# Generated by FakeRAM 2.0
VERSION 5.7 ;
BUSBITCHARS "[]" ;
PROPERTYDEFINITIONS
  MACRO width INTEGER ;
  MACRO depth INTEGER ;
  MACRO banks INTEGER ;
END PROPERTYDEFINITIONS
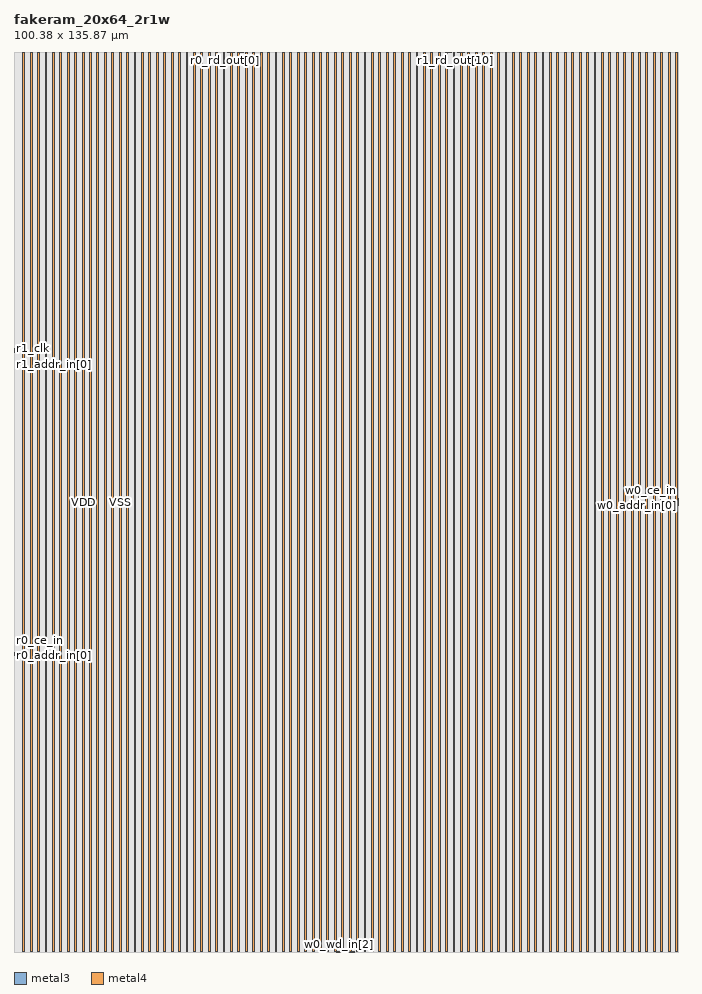
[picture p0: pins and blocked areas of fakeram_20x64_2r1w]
MACRO fakeram_20x64_2r1w
  PROPERTY width 20 ;
  PROPERTY depth 64 ;
  PROPERTY banks 1 ;
  FOREIGN fakeram_20x64_2r1w 0 0 ;
  SYMMETRY X Y R90 ;
  SIZE 100.380 BY 135.870 ;
  CLASS BLOCK ;
  PIN r0_addr_in[0]
    DIRECTION INPUT ;
    USE SIGNAL ;
    SHAPE ABUTMENT ;
    PORT
      LAYER metal3 ;
      RECT 0.000 44.800 0.070 44.870 ;
    END
  END r0_addr_in[0]
  PIN r0_addr_in[1]
    DIRECTION INPUT ;
    USE SIGNAL ;
    SHAPE ABUTMENT ;
    PORT
      LAYER metal3 ;
      RECT 0.000 44.940 0.070 45.010 ;
    END
  END r0_addr_in[1]
  PIN r0_addr_in[2]
    DIRECTION INPUT ;
    USE SIGNAL ;
    SHAPE ABUTMENT ;
    PORT
      LAYER metal3 ;
      RECT 0.000 45.080 0.070 45.150 ;
    END
  END r0_addr_in[2]
  PIN r0_addr_in[3]
    DIRECTION INPUT ;
    USE SIGNAL ;
    SHAPE ABUTMENT ;
    PORT
      LAYER metal3 ;
      RECT 0.000 45.220 0.070 45.290 ;
    END
  END r0_addr_in[3]
  PIN r0_addr_in[4]
    DIRECTION INPUT ;
    USE SIGNAL ;
    SHAPE ABUTMENT ;
    PORT
      LAYER metal3 ;
      RECT 0.000 45.360 0.070 45.430 ;
    END
  END r0_addr_in[4]
  PIN r0_addr_in[5]
    DIRECTION INPUT ;
    USE SIGNAL ;
    SHAPE ABUTMENT ;
    PORT
      LAYER metal3 ;
      RECT 0.000 45.500 0.070 45.570 ;
    END
  END r0_addr_in[5]
  PIN r0_ce_in
    DIRECTION INPUT ;
    USE SIGNAL ;
    SHAPE ABUTMENT ;
    PORT
      LAYER metal3 ;
      RECT 0.000 45.780 0.070 45.850 ;
    END
  END r0_ce_in
  PIN r0_clk
    DIRECTION INPUT ;
    USE SIGNAL ;
    SHAPE ABUTMENT ;
    PORT
      LAYER metal3 ;
      RECT 0.000 45.920 0.070 45.990 ;
    END
  END r0_clk
  PIN r0_rd_out[0]
    DIRECTION OUTPUT ;
    USE SIGNAL ;
    SHAPE ABUTMENT ;
    PORT
      LAYER metal3 ;
      RECT 31.885 135.800 31.955 135.870 ;
    END
  END r0_rd_out[0]
  PIN r0_rd_out[1]
    DIRECTION OUTPUT ;
    USE SIGNAL ;
    SHAPE ABUTMENT ;
    PORT
      LAYER metal3 ;
      RECT 32.025 135.800 32.095 135.870 ;
    END
  END r0_rd_out[1]
  PIN r0_rd_out[2]
    DIRECTION OUTPUT ;
    USE SIGNAL ;
    SHAPE ABUTMENT ;
    PORT
      LAYER metal3 ;
      RECT 32.165 135.800 32.235 135.870 ;
    END
  END r0_rd_out[2]
  PIN r0_rd_out[3]
    DIRECTION OUTPUT ;
    USE SIGNAL ;
    SHAPE ABUTMENT ;
    PORT
      LAYER metal3 ;
      RECT 32.305 135.800 32.375 135.870 ;
    END
  END r0_rd_out[3]
  PIN r0_rd_out[4]
    DIRECTION OUTPUT ;
    USE SIGNAL ;
    SHAPE ABUTMENT ;
    PORT
      LAYER metal3 ;
      RECT 32.445 135.800 32.515 135.870 ;
    END
  END r0_rd_out[4]
  PIN r0_rd_out[5]
    DIRECTION OUTPUT ;
    USE SIGNAL ;
    SHAPE ABUTMENT ;
    PORT
      LAYER metal3 ;
      RECT 32.585 135.800 32.655 135.870 ;
    END
  END r0_rd_out[5]
  PIN r0_rd_out[6]
    DIRECTION OUTPUT ;
    USE SIGNAL ;
    SHAPE ABUTMENT ;
    PORT
      LAYER metal3 ;
      RECT 32.725 135.800 32.795 135.870 ;
    END
  END r0_rd_out[6]
  PIN r0_rd_out[7]
    DIRECTION OUTPUT ;
    USE SIGNAL ;
    SHAPE ABUTMENT ;
    PORT
      LAYER metal3 ;
      RECT 32.865 135.800 32.935 135.870 ;
    END
  END r0_rd_out[7]
  PIN r0_rd_out[8]
    DIRECTION OUTPUT ;
    USE SIGNAL ;
    SHAPE ABUTMENT ;
    PORT
      LAYER metal3 ;
      RECT 33.005 135.800 33.075 135.870 ;
    END
  END r0_rd_out[8]
  PIN r0_rd_out[9]
    DIRECTION OUTPUT ;
    USE SIGNAL ;
    SHAPE ABUTMENT ;
    PORT
      LAYER metal3 ;
      RECT 33.145 135.800 33.215 135.870 ;
    END
  END r0_rd_out[9]
  PIN r0_rd_out[10]
    DIRECTION OUTPUT ;
    USE SIGNAL ;
    SHAPE ABUTMENT ;
    PORT
      LAYER metal3 ;
      RECT 33.285 135.800 33.355 135.870 ;
    END
  END r0_rd_out[10]
  PIN r0_rd_out[11]
    DIRECTION OUTPUT ;
    USE SIGNAL ;
    SHAPE ABUTMENT ;
    PORT
      LAYER metal3 ;
      RECT 33.425 135.800 33.495 135.870 ;
    END
  END r0_rd_out[11]
  PIN r0_rd_out[12]
    DIRECTION OUTPUT ;
    USE SIGNAL ;
    SHAPE ABUTMENT ;
    PORT
      LAYER metal3 ;
      RECT 33.565 135.800 33.635 135.870 ;
    END
  END r0_rd_out[12]
  PIN r0_rd_out[13]
    DIRECTION OUTPUT ;
    USE SIGNAL ;
    SHAPE ABUTMENT ;
    PORT
      LAYER metal3 ;
      RECT 33.705 135.800 33.775 135.870 ;
    END
  END r0_rd_out[13]
  PIN r0_rd_out[14]
    DIRECTION OUTPUT ;
    USE SIGNAL ;
    SHAPE ABUTMENT ;
    PORT
      LAYER metal3 ;
      RECT 33.845 135.800 33.915 135.870 ;
    END
  END r0_rd_out[14]
  PIN r0_rd_out[15]
    DIRECTION OUTPUT ;
    USE SIGNAL ;
    SHAPE ABUTMENT ;
    PORT
      LAYER metal3 ;
      RECT 33.985 135.800 34.055 135.870 ;
    END
  END r0_rd_out[15]
  PIN r0_rd_out[16]
    DIRECTION OUTPUT ;
    USE SIGNAL ;
    SHAPE ABUTMENT ;
    PORT
      LAYER metal3 ;
      RECT 34.125 135.800 34.195 135.870 ;
    END
  END r0_rd_out[16]
  PIN r0_rd_out[17]
    DIRECTION OUTPUT ;
    USE SIGNAL ;
    SHAPE ABUTMENT ;
    PORT
      LAYER metal3 ;
      RECT 34.265 135.800 34.335 135.870 ;
    END
  END r0_rd_out[17]
  PIN r0_rd_out[18]
    DIRECTION OUTPUT ;
    USE SIGNAL ;
    SHAPE ABUTMENT ;
    PORT
      LAYER metal3 ;
      RECT 34.405 135.800 34.475 135.870 ;
    END
  END r0_rd_out[18]
  PIN r0_rd_out[19]
    DIRECTION OUTPUT ;
    USE SIGNAL ;
    SHAPE ABUTMENT ;
    PORT
      LAYER metal3 ;
      RECT 34.545 135.800 34.615 135.870 ;
    END
  END r0_rd_out[19]
  PIN r1_addr_in[0]
    DIRECTION INPUT ;
    USE SIGNAL ;
    SHAPE ABUTMENT ;
    PORT
      LAYER metal3 ;
      RECT 0.000 89.880 0.070 89.950 ;
    END
  END r1_addr_in[0]
  PIN r1_addr_in[1]
    DIRECTION INPUT ;
    USE SIGNAL ;
    SHAPE ABUTMENT ;
    PORT
      LAYER metal3 ;
      RECT 0.000 90.020 0.070 90.090 ;
    END
  END r1_addr_in[1]
  PIN r1_addr_in[2]
    DIRECTION INPUT ;
    USE SIGNAL ;
    SHAPE ABUTMENT ;
    PORT
      LAYER metal3 ;
      RECT 0.000 90.160 0.070 90.230 ;
    END
  END r1_addr_in[2]
  PIN r1_addr_in[3]
    DIRECTION INPUT ;
    USE SIGNAL ;
    SHAPE ABUTMENT ;
    PORT
      LAYER metal3 ;
      RECT 0.000 90.300 0.070 90.370 ;
    END
  END r1_addr_in[3]
  PIN r1_addr_in[4]
    DIRECTION INPUT ;
    USE SIGNAL ;
    SHAPE ABUTMENT ;
    PORT
      LAYER metal3 ;
      RECT 0.000 90.440 0.070 90.510 ;
    END
  END r1_addr_in[4]
  PIN r1_addr_in[5]
    DIRECTION INPUT ;
    USE SIGNAL ;
    SHAPE ABUTMENT ;
    PORT
      LAYER metal3 ;
      RECT 0.000 90.580 0.070 90.650 ;
    END
  END r1_addr_in[5]
  PIN r1_ce_in
    DIRECTION INPUT ;
    USE SIGNAL ;
    SHAPE ABUTMENT ;
    PORT
      LAYER metal3 ;
      RECT 0.000 90.860 0.070 90.930 ;
    END
  END r1_ce_in
  PIN r1_clk
    DIRECTION INPUT ;
    USE SIGNAL ;
    SHAPE ABUTMENT ;
    PORT
      LAYER metal3 ;
      RECT 0.000 91.000 0.070 91.070 ;
    END
  END r1_clk
  PIN r1_rd_out[0]
    DIRECTION OUTPUT ;
    USE SIGNAL ;
    SHAPE ABUTMENT ;
    PORT
      LAYER metal3 ;
      RECT 65.205 135.800 65.275 135.870 ;
    END
  END r1_rd_out[0]
  PIN r1_rd_out[1]
    DIRECTION OUTPUT ;
    USE SIGNAL ;
    SHAPE ABUTMENT ;
    PORT
      LAYER metal3 ;
      RECT 65.345 135.800 65.415 135.870 ;
    END
  END r1_rd_out[1]
  PIN r1_rd_out[2]
    DIRECTION OUTPUT ;
    USE SIGNAL ;
    SHAPE ABUTMENT ;
    PORT
      LAYER metal3 ;
      RECT 65.485 135.800 65.555 135.870 ;
    END
  END r1_rd_out[2]
  PIN r1_rd_out[3]
    DIRECTION OUTPUT ;
    USE SIGNAL ;
    SHAPE ABUTMENT ;
    PORT
      LAYER metal3 ;
      RECT 65.625 135.800 65.695 135.870 ;
    END
  END r1_rd_out[3]
  PIN r1_rd_out[4]
    DIRECTION OUTPUT ;
    USE SIGNAL ;
    SHAPE ABUTMENT ;
    PORT
      LAYER metal3 ;
      RECT 65.765 135.800 65.835 135.870 ;
    END
  END r1_rd_out[4]
  PIN r1_rd_out[5]
    DIRECTION OUTPUT ;
    USE SIGNAL ;
    SHAPE ABUTMENT ;
    PORT
      LAYER metal3 ;
      RECT 65.905 135.800 65.975 135.870 ;
    END
  END r1_rd_out[5]
  PIN r1_rd_out[6]
    DIRECTION OUTPUT ;
    USE SIGNAL ;
    SHAPE ABUTMENT ;
    PORT
      LAYER metal3 ;
      RECT 66.045 135.800 66.115 135.870 ;
    END
  END r1_rd_out[6]
  PIN r1_rd_out[7]
    DIRECTION OUTPUT ;
    USE SIGNAL ;
    SHAPE ABUTMENT ;
    PORT
      LAYER metal3 ;
      RECT 66.185 135.800 66.255 135.870 ;
    END
  END r1_rd_out[7]
  PIN r1_rd_out[8]
    DIRECTION OUTPUT ;
    USE SIGNAL ;
    SHAPE ABUTMENT ;
    PORT
      LAYER metal3 ;
      RECT 66.325 135.800 66.395 135.870 ;
    END
  END r1_rd_out[8]
  PIN r1_rd_out[9]
    DIRECTION OUTPUT ;
    USE SIGNAL ;
    SHAPE ABUTMENT ;
    PORT
      LAYER metal3 ;
      RECT 66.465 135.800 66.535 135.870 ;
    END
  END r1_rd_out[9]
  PIN r1_rd_out[10]
    DIRECTION OUTPUT ;
    USE SIGNAL ;
    SHAPE ABUTMENT ;
    PORT
      LAYER metal3 ;
      RECT 66.605 135.800 66.675 135.870 ;
    END
  END r1_rd_out[10]
  PIN r1_rd_out[11]
    DIRECTION OUTPUT ;
    USE SIGNAL ;
    SHAPE ABUTMENT ;
    PORT
      LAYER metal3 ;
      RECT 66.745 135.800 66.815 135.870 ;
    END
  END r1_rd_out[11]
  PIN r1_rd_out[12]
    DIRECTION OUTPUT ;
    USE SIGNAL ;
    SHAPE ABUTMENT ;
    PORT
      LAYER metal3 ;
      RECT 66.885 135.800 66.955 135.870 ;
    END
  END r1_rd_out[12]
  PIN r1_rd_out[13]
    DIRECTION OUTPUT ;
    USE SIGNAL ;
    SHAPE ABUTMENT ;
    PORT
      LAYER metal3 ;
      RECT 67.025 135.800 67.095 135.870 ;
    END
  END r1_rd_out[13]
  PIN r1_rd_out[14]
    DIRECTION OUTPUT ;
    USE SIGNAL ;
    SHAPE ABUTMENT ;
    PORT
      LAYER metal3 ;
      RECT 67.165 135.800 67.235 135.870 ;
    END
  END r1_rd_out[14]
  PIN r1_rd_out[15]
    DIRECTION OUTPUT ;
    USE SIGNAL ;
    SHAPE ABUTMENT ;
    PORT
      LAYER metal3 ;
      RECT 67.305 135.800 67.375 135.870 ;
    END
  END r1_rd_out[15]
  PIN r1_rd_out[16]
    DIRECTION OUTPUT ;
    USE SIGNAL ;
    SHAPE ABUTMENT ;
    PORT
      LAYER metal3 ;
      RECT 67.445 135.800 67.515 135.870 ;
    END
  END r1_rd_out[16]
  PIN r1_rd_out[17]
    DIRECTION OUTPUT ;
    USE SIGNAL ;
    SHAPE ABUTMENT ;
    PORT
      LAYER metal3 ;
      RECT 67.585 135.800 67.655 135.870 ;
    END
  END r1_rd_out[17]
  PIN r1_rd_out[18]
    DIRECTION OUTPUT ;
    USE SIGNAL ;
    SHAPE ABUTMENT ;
    PORT
      LAYER metal3 ;
      RECT 67.725 135.800 67.795 135.870 ;
    END
  END r1_rd_out[18]
  PIN r1_rd_out[19]
    DIRECTION OUTPUT ;
    USE SIGNAL ;
    SHAPE ABUTMENT ;
    PORT
      LAYER metal3 ;
      RECT 67.865 135.800 67.935 135.870 ;
    END
  END r1_rd_out[19]
  PIN w0_addr_in[0]
    DIRECTION INPUT ;
    USE SIGNAL ;
    SHAPE ABUTMENT ;
    PORT
      LAYER metal3 ;
      RECT 100.310 67.340 100.380 67.410 ;
    END
  END w0_addr_in[0]
  PIN w0_addr_in[1]
    DIRECTION INPUT ;
    USE SIGNAL ;
    SHAPE ABUTMENT ;
    PORT
      LAYER metal3 ;
      RECT 100.310 67.480 100.380 67.550 ;
    END
  END w0_addr_in[1]
  PIN w0_addr_in[2]
    DIRECTION INPUT ;
    USE SIGNAL ;
    SHAPE ABUTMENT ;
    PORT
      LAYER metal3 ;
      RECT 100.310 67.620 100.380 67.690 ;
    END
  END w0_addr_in[2]
  PIN w0_addr_in[3]
    DIRECTION INPUT ;
    USE SIGNAL ;
    SHAPE ABUTMENT ;
    PORT
      LAYER metal3 ;
      RECT 100.310 67.760 100.380 67.830 ;
    END
  END w0_addr_in[3]
  PIN w0_addr_in[4]
    DIRECTION INPUT ;
    USE SIGNAL ;
    SHAPE ABUTMENT ;
    PORT
      LAYER metal3 ;
      RECT 100.310 67.900 100.380 67.970 ;
    END
  END w0_addr_in[4]
  PIN w0_addr_in[5]
    DIRECTION INPUT ;
    USE SIGNAL ;
    SHAPE ABUTMENT ;
    PORT
      LAYER metal3 ;
      RECT 100.310 68.040 100.380 68.110 ;
    END
  END w0_addr_in[5]
  PIN w0_we_in
    DIRECTION INPUT ;
    USE SIGNAL ;
    SHAPE ABUTMENT ;
    PORT
      LAYER metal3 ;
      RECT 100.310 68.320 100.380 68.390 ;
    END
  END w0_we_in
  PIN w0_ce_in
    DIRECTION INPUT ;
    USE SIGNAL ;
    SHAPE ABUTMENT ;
    PORT
      LAYER metal3 ;
      RECT 100.310 68.460 100.380 68.530 ;
    END
  END w0_ce_in
  PIN w0_clk
    DIRECTION INPUT ;
    USE SIGNAL ;
    SHAPE ABUTMENT ;
    PORT
      LAYER metal3 ;
      RECT 100.310 68.600 100.380 68.670 ;
    END
  END w0_clk
  PIN w0_wd_in[0]
    DIRECTION INPUT ;
    USE SIGNAL ;
    SHAPE ABUTMENT ;
    PORT
      LAYER metal3 ;
      RECT 48.685 0.000 48.755 0.070 ;
    END
  END w0_wd_in[0]
  PIN w0_wd_in[1]
    DIRECTION INPUT ;
    USE SIGNAL ;
    SHAPE ABUTMENT ;
    PORT
      LAYER metal3 ;
      RECT 48.825 0.000 48.895 0.070 ;
    END
  END w0_wd_in[1]
  PIN w0_wd_in[2]
    DIRECTION INPUT ;
    USE SIGNAL ;
    SHAPE ABUTMENT ;
    PORT
      LAYER metal3 ;
      RECT 48.965 0.000 49.035 0.070 ;
    END
  END w0_wd_in[2]
  PIN w0_wd_in[3]
    DIRECTION INPUT ;
    USE SIGNAL ;
    SHAPE ABUTMENT ;
    PORT
      LAYER metal3 ;
      RECT 49.105 0.000 49.175 0.070 ;
    END
  END w0_wd_in[3]
  PIN w0_wd_in[4]
    DIRECTION INPUT ;
    USE SIGNAL ;
    SHAPE ABUTMENT ;
    PORT
      LAYER metal3 ;
      RECT 49.245 0.000 49.315 0.070 ;
    END
  END w0_wd_in[4]
  PIN w0_wd_in[5]
    DIRECTION INPUT ;
    USE SIGNAL ;
    SHAPE ABUTMENT ;
    PORT
      LAYER metal3 ;
      RECT 49.385 0.000 49.455 0.070 ;
    END
  END w0_wd_in[5]
  PIN w0_wd_in[6]
    DIRECTION INPUT ;
    USE SIGNAL ;
    SHAPE ABUTMENT ;
    PORT
      LAYER metal3 ;
      RECT 49.525 0.000 49.595 0.070 ;
    END
  END w0_wd_in[6]
  PIN w0_wd_in[7]
    DIRECTION INPUT ;
    USE SIGNAL ;
    SHAPE ABUTMENT ;
    PORT
      LAYER metal3 ;
      RECT 49.665 0.000 49.735 0.070 ;
    END
  END w0_wd_in[7]
  PIN w0_wd_in[8]
    DIRECTION INPUT ;
    USE SIGNAL ;
    SHAPE ABUTMENT ;
    PORT
      LAYER metal3 ;
      RECT 49.805 0.000 49.875 0.070 ;
    END
  END w0_wd_in[8]
  PIN w0_wd_in[9]
    DIRECTION INPUT ;
    USE SIGNAL ;
    SHAPE ABUTMENT ;
    PORT
      LAYER metal3 ;
      RECT 49.945 0.000 50.015 0.070 ;
    END
  END w0_wd_in[9]
  PIN w0_wd_in[10]
    DIRECTION INPUT ;
    USE SIGNAL ;
    SHAPE ABUTMENT ;
    PORT
      LAYER metal3 ;
      RECT 50.085 0.000 50.155 0.070 ;
    END
  END w0_wd_in[10]
  PIN w0_wd_in[11]
    DIRECTION INPUT ;
    USE SIGNAL ;
    SHAPE ABUTMENT ;
    PORT
      LAYER metal3 ;
      RECT 50.225 0.000 50.295 0.070 ;
    END
  END w0_wd_in[11]
  PIN w0_wd_in[12]
    DIRECTION INPUT ;
    USE SIGNAL ;
    SHAPE ABUTMENT ;
    PORT
      LAYER metal3 ;
      RECT 50.365 0.000 50.435 0.070 ;
    END
  END w0_wd_in[12]
  PIN w0_wd_in[13]
    DIRECTION INPUT ;
    USE SIGNAL ;
    SHAPE ABUTMENT ;
    PORT
      LAYER metal3 ;
      RECT 50.505 0.000 50.575 0.070 ;
    END
  END w0_wd_in[13]
  PIN w0_wd_in[14]
    DIRECTION INPUT ;
    USE SIGNAL ;
    SHAPE ABUTMENT ;
    PORT
      LAYER metal3 ;
      RECT 50.645 0.000 50.715 0.070 ;
    END
  END w0_wd_in[14]
  PIN w0_wd_in[15]
    DIRECTION INPUT ;
    USE SIGNAL ;
    SHAPE ABUTMENT ;
    PORT
      LAYER metal3 ;
      RECT 50.785 0.000 50.855 0.070 ;
    END
  END w0_wd_in[15]
  PIN w0_wd_in[16]
    DIRECTION INPUT ;
    USE SIGNAL ;
    SHAPE ABUTMENT ;
    PORT
      LAYER metal3 ;
      RECT 50.925 0.000 50.995 0.070 ;
    END
  END w0_wd_in[16]
  PIN w0_wd_in[17]
    DIRECTION INPUT ;
    USE SIGNAL ;
    SHAPE ABUTMENT ;
    PORT
      LAYER metal3 ;
      RECT 51.065 0.000 51.135 0.070 ;
    END
  END w0_wd_in[17]
  PIN w0_wd_in[18]
    DIRECTION INPUT ;
    USE SIGNAL ;
    SHAPE ABUTMENT ;
    PORT
      LAYER metal3 ;
      RECT 51.205 0.000 51.275 0.070 ;
    END
  END w0_wd_in[18]
  PIN w0_wd_in[19]
    DIRECTION INPUT ;
    USE SIGNAL ;
    SHAPE ABUTMENT ;
    PORT
      LAYER metal3 ;
      RECT 51.345 0.000 51.415 0.070 ;
    END
  END w0_wd_in[19]
  PIN VSS
    DIRECTION INOUT ;
    USE GROUND ;
    PORT
      LAYER metal4 ;
      RECT 2.450 0.140 2.730 135.730 ;
      RECT 4.690 0.140 4.970 135.730 ;
      RECT 6.930 0.140 7.210 135.730 ;
      RECT 9.170 0.140 9.450 135.730 ;
      RECT 11.410 0.140 11.690 135.730 ;
      RECT 13.650 0.140 13.930 135.730 ;
      RECT 15.890 0.140 16.170 135.730 ;
      RECT 18.130 0.140 18.410 135.730 ;
      RECT 20.370 0.140 20.650 135.730 ;
      RECT 22.610 0.140 22.890 135.730 ;
      RECT 24.850 0.140 25.130 135.730 ;
      RECT 27.090 0.140 27.370 135.730 ;
      RECT 29.330 0.140 29.610 135.730 ;
      RECT 31.570 0.140 31.850 135.730 ;
      RECT 33.810 0.140 34.090 135.730 ;
      RECT 36.050 0.140 36.330 135.730 ;
      RECT 38.290 0.140 38.570 135.730 ;
      RECT 40.530 0.140 40.810 135.730 ;
      RECT 42.770 0.140 43.050 135.730 ;
      RECT 45.010 0.140 45.290 135.730 ;
      RECT 47.250 0.140 47.530 135.730 ;
      RECT 49.490 0.140 49.770 135.730 ;
      RECT 51.730 0.140 52.010 135.730 ;
      RECT 53.970 0.140 54.250 135.730 ;
      RECT 56.210 0.140 56.490 135.730 ;
      RECT 58.450 0.140 58.730 135.730 ;
      RECT 60.690 0.140 60.970 135.730 ;
      RECT 62.930 0.140 63.210 135.730 ;
      RECT 65.170 0.140 65.450 135.730 ;
      RECT 67.410 0.140 67.690 135.730 ;
      RECT 69.650 0.140 69.930 135.730 ;
      RECT 71.890 0.140 72.170 135.730 ;
      RECT 74.130 0.140 74.410 135.730 ;
      RECT 76.370 0.140 76.650 135.730 ;
      RECT 78.610 0.140 78.890 135.730 ;
      RECT 80.850 0.140 81.130 135.730 ;
      RECT 83.090 0.140 83.370 135.730 ;
      RECT 85.330 0.140 85.610 135.730 ;
      RECT 87.570 0.140 87.850 135.730 ;
      RECT 89.810 0.140 90.090 135.730 ;
      RECT 92.050 0.140 92.330 135.730 ;
      RECT 94.290 0.140 94.570 135.730 ;
      RECT 96.530 0.140 96.810 135.730 ;
      RECT 98.770 0.140 99.050 135.730 ;
    END
  END VSS
  PIN VDD
    DIRECTION INOUT ;
    USE POWER ;
    PORT
      LAYER metal4 ;
      RECT 1.330 0.140 1.610 135.730 ;
      RECT 3.570 0.140 3.850 135.730 ;
      RECT 5.810 0.140 6.090 135.730 ;
      RECT 8.050 0.140 8.330 135.730 ;
      RECT 10.290 0.140 10.570 135.730 ;
      RECT 12.530 0.140 12.810 135.730 ;
      RECT 14.770 0.140 15.050 135.730 ;
      RECT 17.010 0.140 17.290 135.730 ;
      RECT 19.250 0.140 19.530 135.730 ;
      RECT 21.490 0.140 21.770 135.730 ;
      RECT 23.730 0.140 24.010 135.730 ;
      RECT 25.970 0.140 26.250 135.730 ;
      RECT 28.210 0.140 28.490 135.730 ;
      RECT 30.450 0.140 30.730 135.730 ;
      RECT 32.690 0.140 32.970 135.730 ;
      RECT 34.930 0.140 35.210 135.730 ;
      RECT 37.170 0.140 37.450 135.730 ;
      RECT 39.410 0.140 39.690 135.730 ;
      RECT 41.650 0.140 41.930 135.730 ;
      RECT 43.890 0.140 44.170 135.730 ;
      RECT 46.130 0.140 46.410 135.730 ;
      RECT 48.370 0.140 48.650 135.730 ;
      RECT 50.610 0.140 50.890 135.730 ;
      RECT 52.850 0.140 53.130 135.730 ;
      RECT 55.090 0.140 55.370 135.730 ;
      RECT 57.330 0.140 57.610 135.730 ;
      RECT 59.570 0.140 59.850 135.730 ;
      RECT 61.810 0.140 62.090 135.730 ;
      RECT 64.050 0.140 64.330 135.730 ;
      RECT 66.290 0.140 66.570 135.730 ;
      RECT 68.530 0.140 68.810 135.730 ;
      RECT 70.770 0.140 71.050 135.730 ;
      RECT 73.010 0.140 73.290 135.730 ;
      RECT 75.250 0.140 75.530 135.730 ;
      RECT 77.490 0.140 77.770 135.730 ;
      RECT 79.730 0.140 80.010 135.730 ;
      RECT 81.970 0.140 82.250 135.730 ;
      RECT 84.210 0.140 84.490 135.730 ;
      RECT 86.450 0.140 86.730 135.730 ;
      RECT 88.690 0.140 88.970 135.730 ;
      RECT 90.930 0.140 91.210 135.730 ;
      RECT 93.170 0.140 93.450 135.730 ;
      RECT 95.410 0.140 95.690 135.730 ;
      RECT 97.650 0.140 97.930 135.730 ;
      RECT 99.890 0.140 100.170 135.730 ;
    END
  END VDD
  OBS
    LAYER metal1 ;
    RECT 0 0 100.380 135.870 ;
    LAYER metal2 ;
    RECT 0 0 100.380 135.870 ;
    LAYER metal3 ;
    RECT 0 0 100.380 135.870 ;
    LAYER metal4 ;
    RECT 0 0 100.380 135.870 ;
    LAYER OVERLAP ;
    RECT 0 0 100.380 135.870 ;
  END
END fakeram_20x64_2r1w

END LIBRARY
